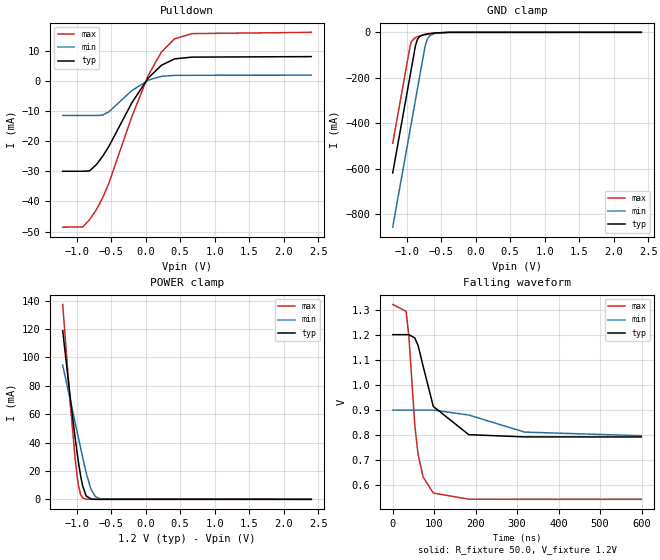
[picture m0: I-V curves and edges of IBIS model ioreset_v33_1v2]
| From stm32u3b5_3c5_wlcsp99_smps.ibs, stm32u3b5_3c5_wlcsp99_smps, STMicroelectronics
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[Model]   ioreset_v33_1v2
Model_type I/O_open_drain
Polarity   Inverting
Enable   Active-Low
| CAP_THRESHOLD on pad IOFT is "UDTCAPC" :
| Rising=30.0% of vddiom   Falling=70.0% of vddiom
| C_comp min and max val. don't necessarily correlate with the min and max pvt
| but are the smallest and greatest pad capacitance found.
| var   typ   min   max
C_comp   2.61606pF  2.50575pF  2.65295pF
|C_comp_pulldown   2.61606pF  2.50575pF  2.65295pF
Vinl = 450.0mV
Vinh = 660.0mV
Vmeas = 600.0mV   | Reference voltage for timing measurements
Cref  = 50.0pF   | Timing specification test load capacitance value
Rref  = 1.0MOhm   | Timing specification test load resistance value
Vref  = 660.0mV   | Timing specification test load voltage
[Model Spec]
| TIME_THRESHOLD on pin ZIV33M is "CMOS" :
| Rising=50.0% of vddiom   Falling=50.0% of vddiom
Vinl 436.50000mV 329.50000mV 482.50000mV
Vinh 746.50000mV 546.50000mV 831.50000mV
| variable   typ   min   max
[Temperature Range] 25.0 130.0 -40.0
| variable   typ   min   max
[Voltage Range] 1.2V 900.0mV 1.32V
| variable   typ   min   max
[POWER Clamp Reference] 1.2V 900.0mV 1.32V
| variable   typ   min   max
[GND Clamp Reference] 0V 0V 0V
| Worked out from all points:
|   slope of the pulldown table from 0 to 0.18 V, typ, clamps not added: 40 ohm
|   GND clamp passes 1 mA (typ) near -0.50 V on its own axis
|   POWER clamp passes 1 mA (typ) near -0.83 V on its own axis
|   falling waveform, R_fixture 50.0, V_fixture 1.2V: 20-80 % time 42.7ns typ, 107ns min, 23.5ns max; typ from 1.2 V to 0.793 V
[POWER Clamp]
-1.2V     118.8mA    94.44mA    137.2mA
-1.09V    71.2mA     69.75mA    67.14mA
-1.02V    43.22mA    54.03mA    28.67mA
-990mV    32.26mA    47.3mA     15.78mA
-970mV    25.49mA    42.81mA    9.257mA
-940mV    16.45mA    36.08mA    3.257mA
-910mV    9.238mA    29.34mA    904.6uA
-860mV    2.387mA    18.53mA    87.46uA
-790mV    204.6uA    7.049mA    3.101uA
-730mV    21.91uA    2.041mA    176.4nA
-660mV    1.594uA    337.6uA    6.241nA
2.4V      0A         0A         0A
[GND Clamp]
-1.2V     -618.9mA   -857.5mA   -488.2mA
-950mV    -193.9mA   -432.5mA   -63.17mA
-930mV    -159.9mA   -398.5mA   -40.85mA
-870mV    -57.94mA   -296.5mA   -22.38mA
-840mV    -28.96mA   -245.5mA   -19.15mA
-800mV    -15.66mA   -177.5mA   -15.7mA
-730mV    -8.799mA   -59.88mA   -10.54mA
-700mV    -7.196mA   -30.65mA   -8.601mA
-660mV    -5.421mA   -13.83mA   -6.302mA
-580mV    -2.708mA   -4.121mA   -2.792mA
-380mV    -61.77uA   -238.6uA   -20.66uA
2.4V      392.8pA    18.37nA    275.9pA
| variable   typ   min   max
[Pullup Reference] 1.2V 900.0mV 1.32V
| variable   typ   min   max
[Pulldown Reference] 0V 0V 0V
[Pulldown]
-1.2V     -29.93mA   -11.33mA   -48.55mA
-910mV    -29.93mA   -11.33mA   -48.48mA
-810mV    -29.8mA    -11.33mA   -46.03mA
-710mV    -27.65mA   -11.33mA   -42.6mA
-620mV    -24.89mA   -11.22mA   -38.69mA
-530mV    -21.58mA   -10.08mA   -33.79mA
-200mV    -7.157mA   -3.075mA   -11.82mA
40mV      1.18mA     424.7uA    2.081mA
230mV     5.395mA    1.701mA    9.799mA
420mV     7.512mA    2.016mA    14.19mA
670mV     8.097mA    2.046mA    15.93mA
2.4V      8.268mA    2.079mA    16.36mA
[Ramp]
dV/dt_r 244.2108mV/730.28736ps 61.61012mV/1.9247ns 467.13673mV/397.36757ps
dV/dt_f 244.21042mV/42.66117ns 61.26967mV/106.6004ns 465.10833mV/23.26979ns
R_load = 50.0
| Removed startup time: 0s 0s 0s  .
| Removed end time: 299.9us.
|[Rising Waveform]
|R_fixture   = 50.0
|V_fixture   = 1.2V
|V_fixture_min = 900.0mV
|V_fixture_max = 1.32V
|  0s  792.98198mV  797.39875mV  544.81958mV
|  6.1us  792.98198mV  797.39875mV  544.81958mV
|  12.2us  792.98198mV  797.39875mV  544.81958mV
|  18.4us  792.98198mV  797.39875mV  544.81958mV
|  24.5us  792.98198mV  797.39875mV  544.81958mV
|  30.6us  792.98198mV  797.39875mV  544.81958mV
|  36.7us  792.98198mV  797.39875mV  544.81958mV
|  42.9us  792.98198mV  797.39875mV  544.81958mV
|  49.0us  792.98198mV  797.39875mV  544.81958mV
|  55.1us  792.98198mV  797.39875mV  544.81958mV
|  59.7us  792.98198mV  797.39875mV  544.81958mV
|  59.8us  792.98198mV  797.39875mV  544.81963mV
|  59.9us  792.98198mV  797.39875mV  1.31999V
|  60.0us  792.98198mV  797.39875mV  1.32000V
|  61.2us  792.98198mV  797.39875mV  1.32000V
|  67.3us  792.98198mV  797.39875mV  1.32000V
|  73.5us  792.98198mV  797.39875mV  1.32000V
|  79.6us  792.98198mV  797.39875mV  1.32000V
|  85.7us  792.98198mV  797.39875mV  1.32000V
|  91.8us  792.98198mV  797.39875mV  1.32000V
|  94.3us  792.98198mV  797.39875mV  1.32000V
|  94.4us  792.98488mV  797.39875mV  1.32000V
|  94.5us  1.19999V  797.39875mV  1.32000V
|  94.6us  1.20000V  797.39875mV  1.32000V
|  98.0us  1.20000V  797.39875mV  1.32000V
|  104.1us  1.20000V  797.39875mV  1.32000V
|  110.2us  1.20000V  797.39875mV  1.32000V
|  116.3us  1.20000V  797.39875mV  1.32000V
|  122.4us  1.20000V  797.39875mV  1.32000V
|  128.6us  1.20000V  797.39875mV  1.32000V
|  134.7us  1.20000V  797.39875mV  1.32000V
|  140.8us  1.20000V  797.39875mV  1.32000V
|  146.9us  1.20000V  797.39875mV  1.32000V
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[Falling Waveform]
R_fixture   = 50.0
V_fixture   = 1.2V
V_fixture_min = 900.0mV
V_fixture_max = 1.32V
0s        1.2V       900mV      1.32V
32.25ns   1.2V       900mV      1.293V
39ns      1.2V       900mV      1.193V
53.3ns    1.187V     900mV      839.4mV
61.15ns   1.157V     900mV      723.5mV
73.4ns    1.074V     900mV      633mV
97.85ns   914.4mV    900mV      569.7mV
183.4ns   802.1mV    880.2mV    545.3mV
318ns     793.2mV    812.3mV    544.8mV
599.3ns   793mV      797.9mV    544.8mV
